VERSION 5.8 ;
BUSBITCHARS "[]" ;
DIVIDERCHAR "/" ;
UNITS
  DATABASE MICRONS 1000 ;
END UNITS
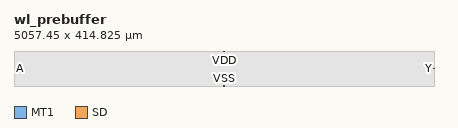
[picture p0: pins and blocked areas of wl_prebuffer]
MACRO wl_prebuffer
  CLASS BLOCK ;
  ORIGIN 0 0 ;
  FOREIGN wl_prebuffer 0 0 ;
  SIZE 5057.45 BY 414.825 ;
  SYMMETRY X Y ;
  PIN A
    DIRECTION INPUT ;
    USE SIGNAL ;
    PORT
      LAYER MT1 ;
        RECT 0 204.9 5 209.9 ;
    END
  END A
  PIN Y
    DIRECTION OUTPUT ;
    USE SIGNAL ;
    PORT
      LAYER MT1 ;
        RECT 5052.45 204.9 5057.45 209.9 ;
    END
  END Y
  PIN VDD
    DIRECTION INOUT ;
    USE POWER ;
    PORT
      LAYER SD ;
        RECT 2526.225 409.825 2531.225 414.825 ;
    END
  END VDD
  PIN VSS
    DIRECTION INOUT ;
    USE GROUND ;
    PORT
      LAYER SD ;
        RECT 2526.225 0 2531.225 5 ;
    END
  END VSS
  OBS
    LAYER SD ;
      RECT 0 0 5057.45 414.825 ;
  END
END wl_prebuffer
END LIBRARY
